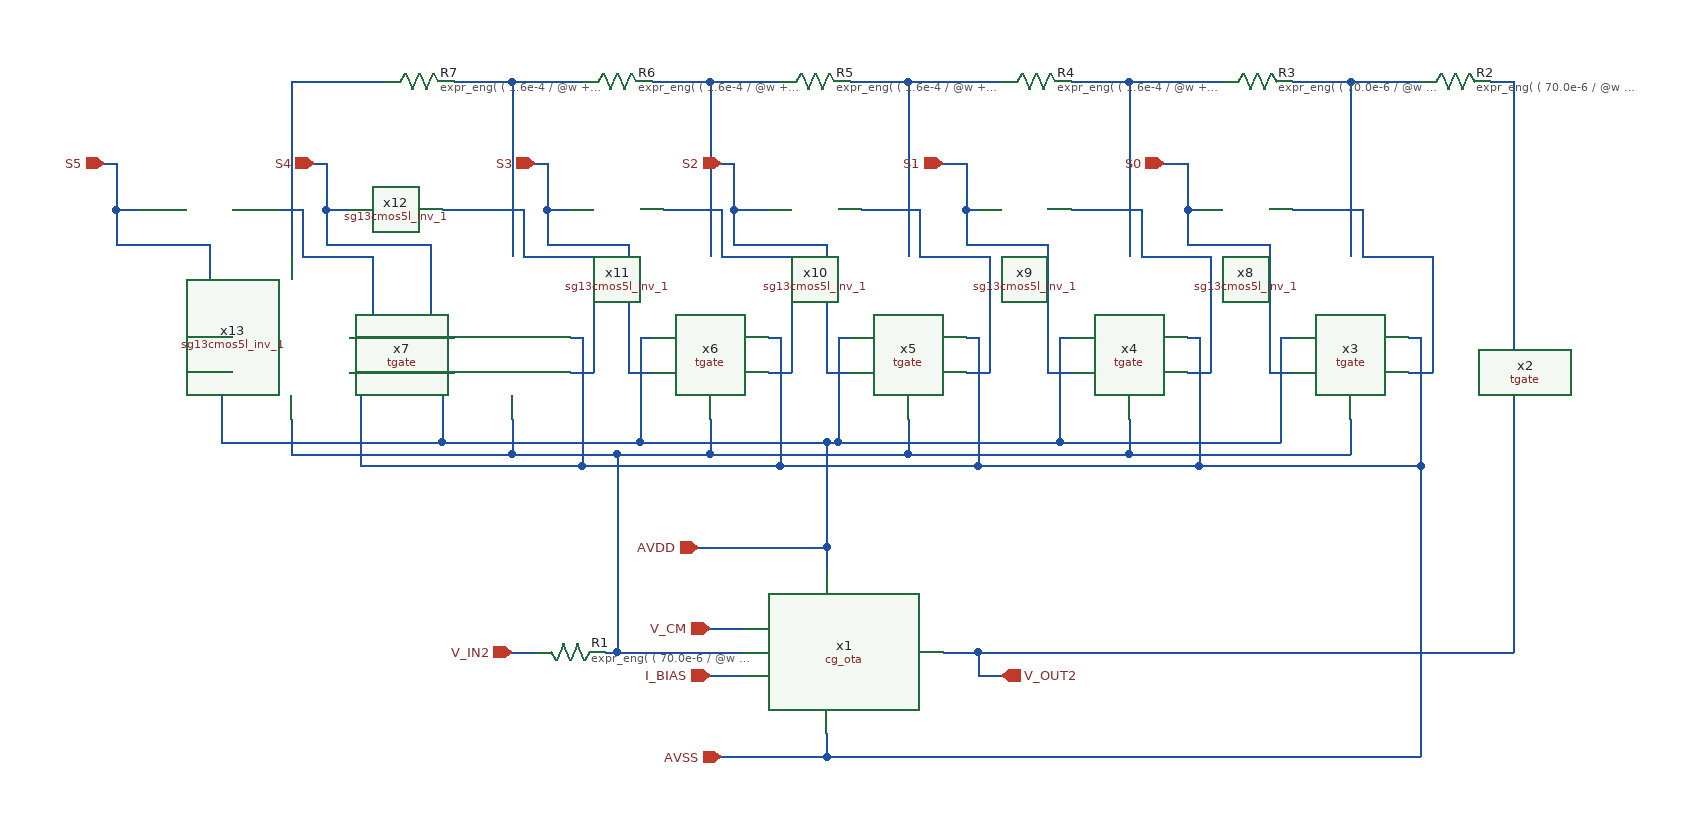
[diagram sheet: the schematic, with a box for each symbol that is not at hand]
v {xschem version=3.4.8RC file_version=1.3}
G {}
K {}
V {}
S {}
F {}
E {}
N -100 30 -70 30 {lab=I_BIAS}
N -270 10 -250 10 {lab=V_IN2}
N -100 -10 -70 -10 {lab=V_CM}
N 450 -480 450 -330 {lab=#net1}
N 450 -480 510 -480 {lab=#net1}
N 400 -480 450 -480 {lab=#net1}
N 260 -480 260 -330 {lab=#net2}
N 260 -480 340 -480 {lab=#net2}
N 210 -480 260 -480 {lab=#net2}
N 70 -480 70 -330 {lab=#net3}
N 70 -480 150 -480 {lab=#net3}
N 20 -480 70 -480 {lab=#net3}
N -100 -480 -100 -330 {lab=#net4}
N -100 -480 -40 -480 {lab=#net4}
N -150 -480 -100 -480 {lab=#net4}
N -270 -480 -270 -330 {lab=#net5}
N -270 -480 -210 -480 {lab=#net5}
N -320 -480 -270 -480 {lab=#net5}
N -460 -480 -460 -330 {lab=#net6}
N -460 -480 -380 -480 {lab=#net6}
N 260 -160 450 -160 {lab=#net7}
N 450 -190 450 -160 {lab=#net7}
N 260 -190 260 -160 {lab=#net7}
N 70 -160 260 -160 {lab=#net7}
N 70 -190 70 -160 {lab=#net7}
N -100 -160 70 -160 {lab=#net7}
N -100 -190 -100 -160 {lab=#net7}
N -180 -160 -100 -160 {lab=#net7}
N -270 -190 -270 -160 {lab=#net7}
N -460 -160 -270 -160 {lab=#net7}
N -460 -190 -460 -160 {lab=#net7}
N -520 -260 -510 -260 {lab=AVDD}
N -330 -260 -320 -260 {lab=AVDD}
N -160 -260 -150 -260 {lab=AVDD}
N 10 -260 20 -260 {lab=AVDD}
N 200 -260 210 -260 {lab=AVDD}
N 390 -260 400 -260 {lab=AVDD}
N -0 -80 -0 -60 {lab=AVDD}
N -410 -260 -400 -260 {lab=AVSS}
N -220 -260 -210 -260 {lab=AVSS}
N -50 -260 -40 -260 {lab=AVSS}
N 120 -260 130 -260 {lab=AVSS}
N 310 -260 320 -260 {lab=AVSS}
N -0 80 -0 100 {lab=AVSS}
N -0 100 510 100 {lab=AVSS}
N -90 100 -0 100 {lab=AVSS}
N -110 -80 -0 -80 {lab=AVDD}
N 500 -260 510 -260 {lab=AVSS}
N 570 -480 590 -480 {lab=V_OUT2}
N 130 10 130 30 {lab=V_OUT2}
N 100 10 130 10 {lab=V_OUT2}
N 130 30 150 30 {lab=V_OUT2}
N -620 -410 -610 -410 {lab=S5}
N -610 -410 -610 -370 {lab=S5}
N -610 -370 -590 -370 {lab=S5}
N -610 -370 -610 -340 {lab=S5}
N -610 -340 -530 -340 {lab=S5}
N -530 -340 -530 -230 {lab=S5}
N -530 -230 -510 -230 {lab=S5}
N -510 -370 -450 -370 {lab=#net8}
N -450 -370 -450 -330 {lab=#net8}
N -450 -330 -390 -330 {lab=#net8}
N -390 -330 -390 -230 {lab=#net8}
N -410 -230 -390 -230 {lab=#net8}
N -440 -410 -430 -410 {lab=S4}
N -430 -410 -430 -370 {lab=S4}
N -430 -370 -410 -370 {lab=S4}
N -430 -370 -430 -340 {lab=S4}
N -430 -340 -340 -340 {lab=S4}
N -340 -340 -340 -230 {lab=S4}
N -340 -230 -320 -230 {lab=S4}
N -330 -370 -260 -370 {lab=#net9}
N -260 -370 -260 -330 {lab=#net9}
N -260 -330 -200 -330 {lab=#net9}
N -200 -330 -200 -230 {lab=#net9}
N -220 -230 -200 -230 {lab=#net9}
N -250 -410 -240 -410 {lab=S3}
N -240 -410 -240 -370 {lab=S3}
N -240 -370 -220 -370 {lab=S3}
N -240 -370 -240 -340 {lab=S3}
N -240 -340 -170 -340 {lab=S3}
N -170 -340 -170 -230 {lab=S3}
N -170 -230 -150 -230 {lab=S3}
N -140 -370 -90 -370 {lab=#net10}
N -90 -370 -90 -330 {lab=#net10}
N -90 -330 -30 -330 {lab=#net10}
N -30 -330 -30 -230 {lab=#net10}
N -50 -230 -30 -230 {lab=#net10}
N -90 -410 -80 -410 {lab=S2}
N -80 -410 -80 -370 {lab=S2}
N -80 -370 -50 -370 {lab=S2}
N -80 -370 -80 -340 {lab=S2}
N -80 -340 0 -340 {lab=S2}
N 0 -340 0 -230 {lab=S2}
N 0 -230 20 -230 {lab=S2}
N 30 -370 80 -370 {lab=#net11}
N 80 -370 80 -330 {lab=#net11}
N 80 -330 140 -330 {lab=#net11}
N 140 -330 140 -230 {lab=#net11}
N 120 -230 140 -230 {lab=#net11}
N 100 -410 120 -410 {lab=S1}
N 120 -410 120 -370 {lab=S1}
N 120 -370 130 -370 {lab=S1}
N 120 -370 120 -340 {lab=S1}
N 120 -340 190 -340 {lab=S1}
N 190 -340 190 -230 {lab=S1}
N 190 -230 210 -230 {lab=S1}
N 210 -370 270 -370 {lab=#net12}
N 270 -370 270 -330 {lab=#net12}
N 270 -330 330 -330 {lab=#net12}
N 330 -330 330 -230 {lab=#net12}
N 310 -230 330 -230 {lab=#net12}
N 290 -410 310 -410 {lab=S0}
N 310 -410 310 -370 {lab=S0}
N 310 -370 320 -370 {lab=S0}
N 310 -370 310 -340 {lab=S0}
N 310 -340 380 -340 {lab=S0}
N 380 -340 380 -230 {lab=S0}
N 380 -230 400 -230 {lab=S0}
N 400 -370 460 -370 {lab=#net13}
N 460 -370 460 -330 {lab=#net13}
N 460 -330 520 -330 {lab=#net13}
N 520 -330 520 -230 {lab=#net13}
N 500 -230 520 -230 {lab=#net13}
N -180 10 -70 10 {lab=#net7}
N -180 -160 -180 10 {lab=#net7}
N -270 -160 -180 -160 {lab=#net7}
N -190 10 -180 10 {lab=#net7}
N 130 10 590 10 {lab=V_OUT2}
N 590 -480 590 10 {lab=V_OUT2}
N -520 -260 -520 -170 {lab=AVDD}
N 200 -170 390 -170 {lab=AVDD}
N 390 -260 390 -170 {lab=AVDD}
N 200 -260 200 -170 {lab=AVDD}
N 10 -170 200 -170 {lab=AVDD}
N 10 -260 10 -170 {lab=AVDD}
N -0 -170 10 -170 {lab=AVDD}
N -160 -260 -160 -170 {lab=AVDD}
N -330 -170 -160 -170 {lab=AVDD}
N -330 -260 -330 -170 {lab=AVDD}
N -520 -170 -330 -170 {lab=AVDD}
N -400 -260 -400 -150 {lab=AVSS}
N -400 -150 -210 -150 {lab=AVSS}
N -210 -260 -210 -150 {lab=AVSS}
N 320 -150 510 -150 {lab=AVSS}
N 510 -260 510 -150 {lab=AVSS}
N 320 -260 320 -150 {lab=AVSS}
N 130 -150 320 -150 {lab=AVSS}
N 130 -260 130 -150 {lab=AVSS}
N -40 -150 130 -150 {lab=AVSS}
N -40 -260 -40 -150 {lab=AVSS}
N -210 -150 -40 -150 {lab=AVSS}
N 510 -150 510 100 {lab=AVSS}
N -0 -170 -0 -80 {lab=AVDD}
N -160 -170 -0 -170 {lab=AVDD}
C {ipin.sym} -100 30 0 0 {name=p1 lab=I_BIAS}
C {ipin.sym} -270 10 0 0 {name=p2 lab=V_IN2}
C {ipin.sym} -100 -10 0 0 {name=p3 lab=V_CM}
C {sg13cmos5l_pr/rhigh.sym} -350 -480 3 0 {name=R7
w=0.5e-6
l=10.72e-6
model=rhigh
body=AVSS
spiceprefix=X
b=0
 m=1
  mm_ok=1
value="expr_eng(  ( 1.6e-4 / @w + 1360.0 * ( (@b + 1)* @l + ( 1.081*@w + 0.18e-6 )*@b ) / ( @w - 0.04e-6 ) ) / @m  )"
}
C {ipin.sym} -90 100 0 0 {name=p4 lab=AVSS}
C {ipin.sym} -110 -80 0 0 {name=p5 lab=AVDD}
C {opin.sym} 150 30 0 0 {name=p6 lab=V_OUT2}
C {ipin.sym} -620 -410 0 0 {name=p17 lab=S5}
C {ipin.sym} -440 -410 0 0 {name=p18 lab=S4}
C {ipin.sym} -250 -410 0 0 {name=p19 lab=S3}
C {ipin.sym} -90 -410 0 0 {name=p20 lab=S2}
C {ipin.sym} 100 -410 0 0 {name=p21 lab=S1}
C {ipin.sym} 290 -410 0 0 {name=p22 lab=S0}
C {sg13cmos5l_pr/rppd.sym} 370 -480 3 0 {name=R3
w=2e-6
l=15.16e-6
model=rppd
body=AVSS
spiceprefix=X
b=0
 m=1
  mm_ok=1
value="expr_eng(  ( 70.0e-6 / @w + 260.0 * ( (@b + 1)* @l + ( 1.081*@w + 0.18e-6 )*@b ) / ( @w + 6.0e-9 ) ) / @m  )"
}
C {sg13cmos5l_pr/rppd.sym} 540 -480 3 0 {name=R2
w=2e-6
l=7e-6
model=rppd
body=AVSS
spiceprefix=X
b=0
 m=1
  mm_ok=1
value="expr_eng(  ( 70.0e-6 / @w + 260.0 * ( (@b + 1)* @l + ( 1.081*@w + 0.18e-6 )*@b ) / ( @w + 6.0e-9 ) ) / @m  )"
}
C {sg13cmos5l_pr/rppd.sym} -220 10 1 0 {name=R1
w=2e-6
l=15.16e-6
model=rppd
body=AVSS
spiceprefix=X
b=0
 m=1
  mm_ok=1
value="expr_eng(  ( 70.0e-6 / @w + 260.0 * ( (@b + 1)* @l + ( 1.081*@w + 0.18e-6 )*@b ) / ( @w + 6.0e-9 ) ) / @m  )"
}
C {sg13cmos5l_stdcells/sg13cmos5l_inv_1.sym} -550 -370 0 0 {name=x13 VDD="AVDD" VSS="AVSS" prefix=sg13cmos5l_ }
C {sg13cmos5l_stdcells/sg13cmos5l_inv_1.sym} -370 -370 0 0 {name=x12 VDD="AVDD" VSS="AVSS" prefix=sg13cmos5l_ }
C {sg13cmos5l_stdcells/sg13cmos5l_inv_1.sym} -180 -370 0 0 {name=x11 VDD="AVDD" VSS="AVSS" prefix=sg13cmos5l_ }
C {sg13cmos5l_stdcells/sg13cmos5l_inv_1.sym} -10 -370 0 0 {name=x10 VDD="AVDD" VSS="AVSS" prefix=sg13cmos5l_ }
C {sg13cmos5l_stdcells/sg13cmos5l_inv_1.sym} 170 -370 0 0 {name=x9 VDD="AVDD" VSS="AVSS" prefix=sg13cmos5l_ }
C {sg13cmos5l_stdcells/sg13cmos5l_inv_1.sym} 360 -370 0 0 {name=x8 VDD="AVDD" VSS="AVSS" prefix=sg13cmos5l_ }
C {/foss/designs/sg13cmos5l_spma_ip__instramp/xschem/tgate/tgate.sym} -310 -230 3 0 {name=x7 l=0.13e-6 wn=0.9e-6 wp=2.7e-6}
C {/foss/designs/sg13cmos5l_spma_ip__instramp/xschem/tgate/tgate.sym} -120 -230 3 0 {name=x6 l=0.13e-6 wn=1.5e-6 wp=4.5e-6}
C {/foss/designs/sg13cmos5l_spma_ip__instramp/xschem/tgate/tgate.sym} 50 -230 3 0 {name=x5 l=0.13e-6 wn=2.2e-6 wp=6.6e-6}
C {/foss/designs/sg13cmos5l_spma_ip__instramp/xschem/tgate/tgate.sym} 220 -230 3 0 {name=x4 l=0.13e-6 wn=2.6e-6 wp=7.8e-6}
C {/foss/designs/sg13cmos5l_spma_ip__instramp/xschem/tgate/tgate.sym} 410 -230 3 0 {name=x3 l=0.13e-6 wn=2.9e-6 wp=8.7e-6}
C {/foss/designs/sg13cmos5l_spma_ip__instramp/xschem/tgate/tgate.sym} 600 -230 3 0 {name=x2 l=0.13e-6 wn=3e-6 wp=9e-6}
C {sg13cmos5l_pr/rhigh.sym} -180 -480 3 0 {name=R6
w=0.5e-6
l=5.3e-6
model=rhigh
body=AVSS
spiceprefix=X
b=0
 m=1
  mm_ok=1
value="expr_eng(  ( 1.6e-4 / @w + 1360.0 * ( (@b + 1)* @l + ( 1.081*@w + 0.18e-6 )*@b ) / ( @w - 0.04e-6 ) ) / @m  )"
}
C {sg13cmos5l_pr/rhigh.sym} -10 -480 3 0 {name=R5
w=0.5e-6
l=2.6e-6
model=rhigh
body=AVSS
spiceprefix=X
b=0
 m=1
  mm_ok=1
value="expr_eng(  ( 1.6e-4 / @w + 1360.0 * ( (@b + 1)* @l + ( 1.081*@w + 0.18e-6 )*@b ) / ( @w - 0.04e-6 ) ) / @m  )"
}
C {sg13cmos5l_pr/rhigh.sym} 180 -480 3 0 {name=R4
w=0.5e-6
l=1.25e-6
model=rhigh
body=AVSS
spiceprefix=X
b=0
 m=1
  mm_ok=1
value="expr_eng(  ( 1.6e-4 / @w + 1360.0 * ( (@b + 1)* @l + ( 1.081*@w + 0.18e-6 )*@b ) / ( @w - 0.04e-6 ) ) / @m  )"
}
C {/foss/designs/sg13cmos5l_spma_ip__instramp/xschem/coarse_gain/cg_ota.sym} 30 30 0 0 {name=x1}
